One B-rep face of a CAD part: STEP entity #703.
In plain terms, the planar face has unit normal (1, 0, 0).
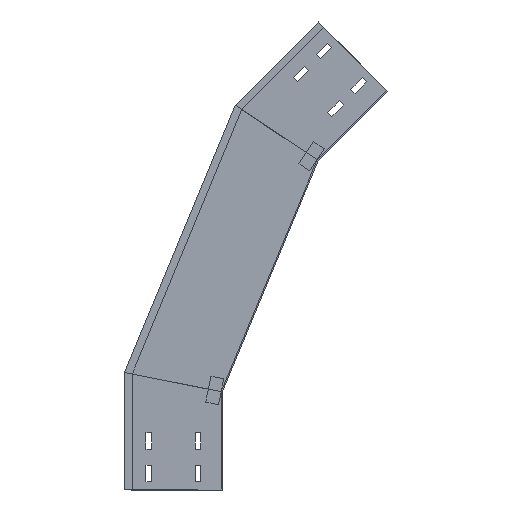
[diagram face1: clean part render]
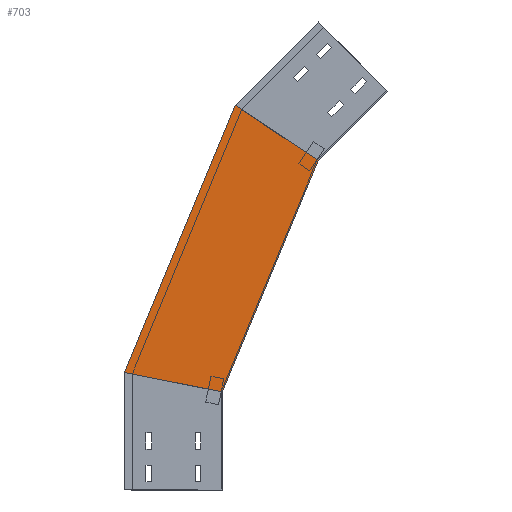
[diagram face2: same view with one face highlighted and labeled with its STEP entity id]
Its self-contained STEP definition (entity closure, numbers rounded to 3 decimals):
#67 = VERTEX_POINT ( 'NONE', #1054 ) ;
#96 = LINE ( 'NONE', #296, #1472 ) ;
#215 = DIRECTION ( 'NONE',  ( 0., -0.831, -0.556 ) ) ;
#296 = CARTESIAN_POINT ( 'NONE',  ( 0., -28.701, 144.291 ) ) ;
#320 = VECTOR ( 'NONE', #1380, 1000. ) ;
#419 = DIRECTION ( 'NONE',  ( 0., -0.383, 0.924 ) ) ;
#461 = CARTESIAN_POINT ( 'NONE',  ( 0., 12.598, 119.585 ) ) ;
#551 = EDGE_CURVE ( 'NONE', #67, #702, #568, .T. ) ;
#568 = LINE ( 'NONE', #1482, #1168 ) ;
#702 = VERTEX_POINT ( 'NONE', #1559 ) ;
#703 = ADVANCED_FACE ( 'NONE', ( #1218 ), #768, .T. ) ;
#736 = DIRECTION ( 'NONE',  ( 0., -0.981, -0.195 ) ) ;
#768 = PLANE ( 'NONE',  #1653 ) ;
#787 = DIRECTION ( 'NONE',  ( 0., 0., -1. ) ) ;
#801 = ORIENTED_EDGE ( 'NONE', *, *, #1418, .F. ) ;
#840 = CARTESIAN_POINT ( 'NONE',  ( 0., -19.404, 588.814 ) ) ;
#842 = ORIENTED_EDGE ( 'NONE', *, *, #551, .F. ) ;
#864 = CARTESIAN_POINT ( 'NONE',  ( 0., -214.035, 458.766 ) ) ;
#905 = CARTESIAN_POINT ( 'NONE',  ( 0., 151.18, 176.988 ) ) ;
#912 = ORIENTED_EDGE ( 'NONE', *, *, #1417, .T. ) ;
#967 = EDGE_CURVE ( 'NONE', #1901, #702, #1328, .T. ) ;
#982 = VERTEX_POINT ( 'NONE', #1953 ) ;
#1054 = CARTESIAN_POINT ( 'NONE',  ( 0., 0., 150. ) ) ;
#1168 = VECTOR ( 'NONE', #419, 1000. ) ;
#1218 = FACE_OUTER_BOUND ( 'NONE', #1885, .T. ) ;
#1328 = LINE ( 'NONE', #864, #1786 ) ;
#1380 = DIRECTION ( 'NONE',  ( 0., -0.383, 0.924 ) ) ;
#1417 = EDGE_CURVE ( 'NONE', #982, #1901, #1548, .T. ) ;
#1418 = EDGE_CURVE ( 'NONE', #982, #67, #96, .T. ) ;
#1472 = VECTOR ( 'NONE', #736, 1000. ) ;
#1482 = CARTESIAN_POINT ( 'NONE',  ( 0., 12.598, 119.585 ) ) ;
#1548 = LINE ( 'NONE', #905, #320 ) ;
#1559 = CARTESIAN_POINT ( 'NONE',  ( 0., -146.568, 503.846 ) ) ;
#1653 = AXIS2_PLACEMENT_3D ( 'NONE', #461, #2012, #787 ) ;
#1786 = VECTOR ( 'NONE', #215, 1000. ) ;
#1885 = EDGE_LOOP ( 'NONE', ( #912, #1924, #842, #801 ) ) ;
#1901 = VERTEX_POINT ( 'NONE', #840 ) ;
#1924 = ORIENTED_EDGE ( 'NONE', *, *, #967, .T. ) ;
#1953 = CARTESIAN_POINT ( 'NONE',  ( 0., 150., 179.837 ) ) ;
#2012 = DIRECTION ( 'NONE',  ( 1., 0., 0. ) ) ;
